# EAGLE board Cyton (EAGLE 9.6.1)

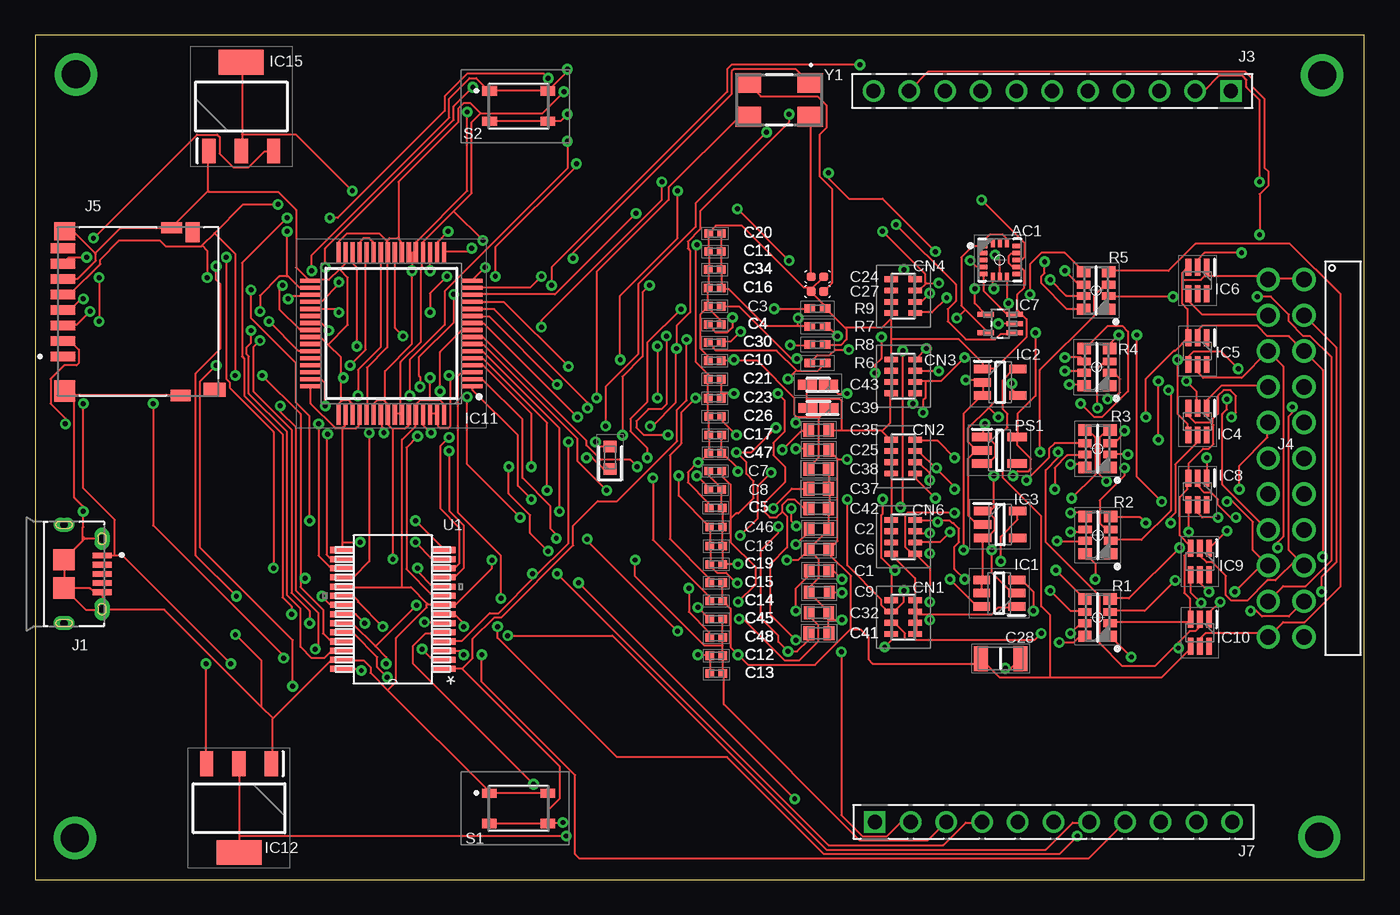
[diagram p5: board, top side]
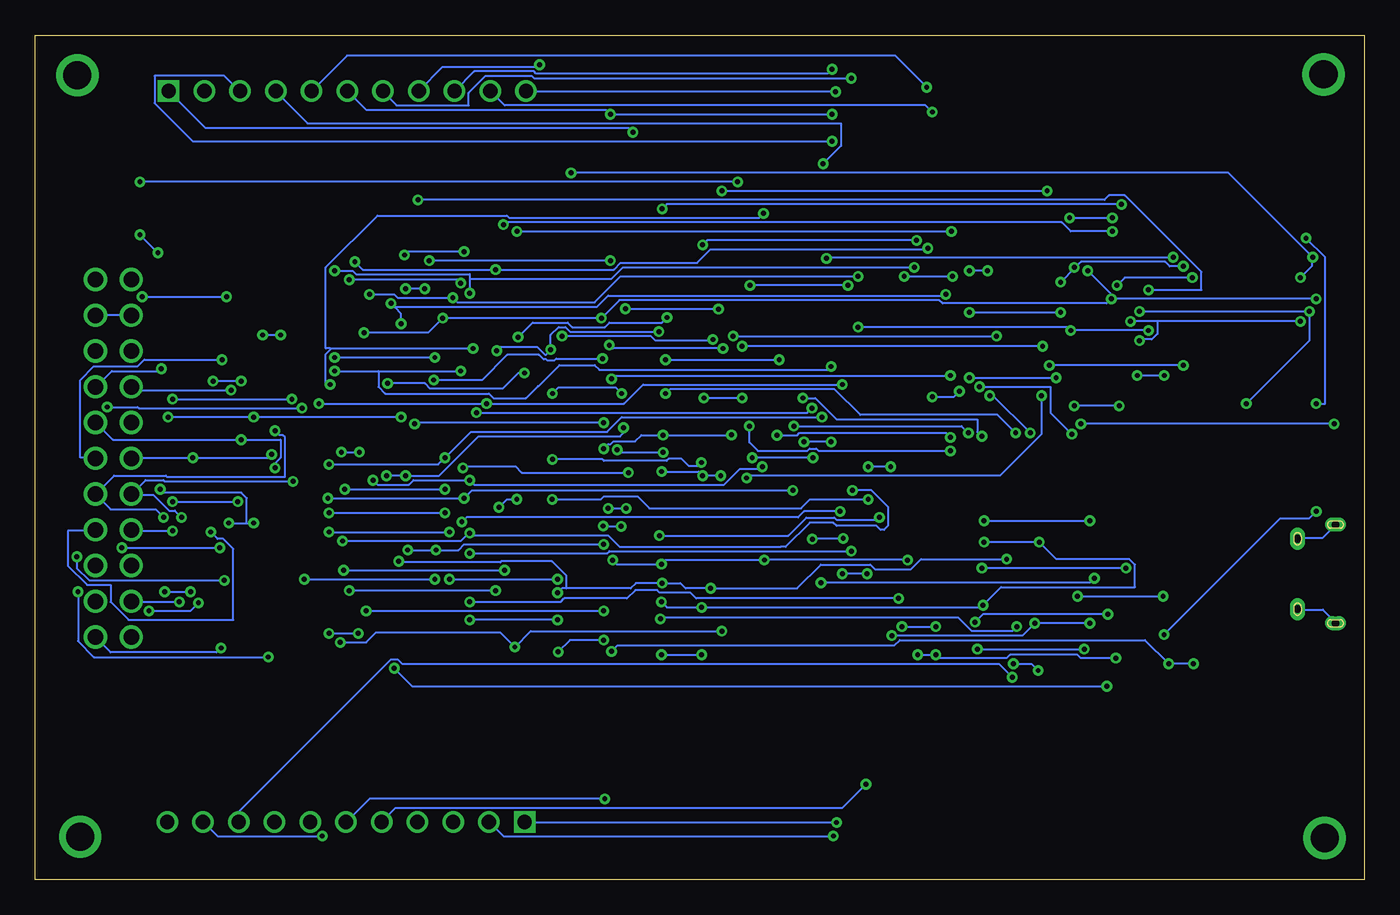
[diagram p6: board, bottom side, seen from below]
Size 94.47 x 60 mm. Coordinates in mm from the lower left corner, seen from the top.
Outline: 0,0 94.47,0 94.47,60 0,60 0,0
Copper layers (1*16): Top 0.035mm / dielectric 1.5mm / Bottom 0.035mm
Design rules "default *": minimum track width 6mil, minimum drill 0.35mm, track to track 6mil, track to pad 6mil, pad to pad 6mil, via to via 6mil, smd to smd 6mil, copper to edge 40mil, drill to drill 6mil, minimum pad ring 10mil, minimum via ring 8mil, stop-mask expansion 0mil, vias tented up to drill 100mm, thermal gap 10mil

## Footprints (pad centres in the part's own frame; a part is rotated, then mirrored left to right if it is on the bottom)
PQFN50P300X300X100-16N = smd 0.6 x 0.3: 1 -1.2,1; 2 -1.2,0.5; 3 -1.2,0; 4 -1.2,-0.5; 5 -1.2,-1; 9 1.2,-1; 10 1.2,-0.5; 11 1.2,0; 12 1.2,0.5; 13 1.2,1 | smd 0.3 x 0.6: 6 -0.5,-1.2; 7 0,-1.2; 8 0.5,-1.2; 14 0.5,1.2; 15 0,1.2; 16 -0.5,1.2
CAPC1608X90N = smd 0.75 x 0.94: 1 -0.7,0; 2 0.7,0
CAPC1005X55N = smd 0.6 x 0.62: 1 -0.46,0; 2 0.46,0
C0402 = smd 0.635 x 0.635: 1 0,0.445; 2 0,-0.445
CAPC3216X125N = smd 0.99 x 1.78: 1 -1.4,0; 2 1.4,0
CAPC1608X95N = smd 0.78 x 0.98: 1 -0.7,0; 2 0.7,0
CAPPM169X100N = smd 1.35 x 0.7: 1 -0.75,0; 2 0.75,0
CA0612KRX7R9BB102 = smd 0.95 x 0.4: 1 -0.85,1.2; 2 -0.85,0.4; 3 -0.85,-0.4; 4 -0.85,-1.2; 5 0.85,-1.2; 6 0.85,-0.4; 7 0.85,0.4; 8 0.85,1.2
SOT95P280X145-6N = smd 1.2 x 0.6: 1 -1.25,0.95; 2 -1.25,0; 3 -1.25,-0.95; 4 1.25,-0.95; 5 1.25,0; 6 1.25,0.95
SOT95P280X145-5N = smd 1.2 x 0.6: 1 -1.25,0.95; 2 -1.25,0; 3 -1.25,-0.95; 4 1.25,-0.95; 5 1.25,0.95
SOT95P280X110-5N = smd 1.25 x 0.6: 1 -1.25,0.95; 2 -1.25,0; 3 -1.25,-0.95; 4 1.25,-0.95; 5 1.25,0.95
SOT65P210X110-6N = smd 1.2 x 0.4: 1 -0.95,0.65; 2 -0.95,0; 3 -0.95,-0.65; 4 0.95,-0.65; 5 0.95,0; 6 0.95,0.65
SOT65P210X110-5N = smd 1.168 x 0.356: 1 -1.041,0.66; 2 -1.041,0; 3 -1.041,-0.66; 4 1.041,-0.66; 5 1.041,0.66
QFP50P1200X1200X120-64N = smd 1.475 x 0.3: 1 -5.738,3.75; 2 -5.738,3.25; 3 -5.738,2.75; 4 -5.738,2.25; 5 -5.738,1.75; 6 -5.738,1.25; 7 -5.738,0.75; 8 -5.738,0.25; 9 -5.738,-0.25; 10 -5.738,-0.75; 11 -5.738,-1.25; 12 -5.738,-1.75; 13 -5.738,-2.25; 14 -5.738,-2.75; 15 -5.738,-3.25; 16 -5.738,-3.75; 33 5.738,-3.75; 34 5.738,-3.25; 35 5.738,-2.75; 36 5.738,-2.25; 37 5.738,-1.75; 38 5.738,-1.25; 39 5.738,-0.75; 40 5.738,-0.25; 41 5.738,0.25; 42 5.738,0.75; 43 5.738,1.25; 44 5.738,1.75; 45 5.738,2.25; 46 5.738,2.75; 47 5.738,3.25; 48 5.738,3.75 | smd 0.3 x 1.475: 17 -3.75,-5.738; 18 -3.25,-5.738; 19 -2.75,-5.738; 20 -2.25,-5.738; 21 -1.75,-5.738; 22 -1.25,-5.738; 23 -0.75,-5.738; 24 -0.25,-5.738; 25 0.25,-5.738; 26 0.75,-5.738; 27 1.25,-5.738; 28 1.75,-5.738; 29 2.25,-5.738; 30 2.75,-5.738; 31 3.25,-5.738; 32 3.75,-5.738; 49 3.75,5.738; 50 3.25,5.738; 51 2.75,5.738; 52 2.25,5.738; 53 1.75,5.738; 54 1.25,5.738; 55 0.75,5.738; 56 0.25,5.738; 57 -0.25,5.738; 58 -0.75,5.738; 59 -1.25,5.738; 60 -1.75,5.738; 61 -2.25,5.738; 62 -2.75,5.738; 63 -3.25,5.738; 64 -3.75,5.738
SOT230P700X180-4N = smd 1.75 x 0.95: 1 -3.15,2.3; 2 -3.15,0; 3 -3.15,-2.3 | smd 1.75 x 3.2: 4 3.15,0
AMPHENOL_10118194-0001LF = smd 0.4 x 1.35: 1 -1.3,2.7; 2 -0.65,2.7; 3 0,2.7; 4 0.65,2.7; 5 1.3,2.7 | drill 0.55 pad 0.61 long: S1 -2.5,2.7; S2 2.5,2.7 | drill 0.5 pad 0.775 long: S3 -3.5,0; S6 3.5,0 | smd 1.5 x 1.55: S4 -1,0; S5 1,0
SAMTEC_SSQ-111-02-G-S = drill 1.016 square: 1 -25.4,0 | drill 1.016: 2 -22.86,0; 3 -20.32,0; 4 -17.78,0; 5 -15.24,0; 6 -12.7,0; 7 -10.16,0; 8 -7.62,0; 9 -5.08,0; 10 -2.54,0; 11 0,0
61302221021 = drill 1.1: 1 12.7,-1.27; 2 12.7,1.27; 3 10.16,-1.27; 4 10.16,1.27; 5 7.62,-1.27; 6 7.62,1.27; 7 5.08,-1.27; 8 5.08,1.27; 9 2.54,-1.27; 10 2.54,1.27; 11 0,-1.27; 12 0,1.27; 13 -2.54,-1.27; 14 -2.54,1.27; 15 -5.08,-1.27; 16 -5.08,1.27; 17 -7.62,-1.27; 18 -7.62,1.27; 19 -10.16,-1.27; 20 -10.16,1.27; 21 -12.7,-1.27; 22 -12.7,1.27
AMPHENOL_1140084168 = smd 0.7 x 1.75: 1 3.2,-0.875; 2 2.1,-0.875; 3 1,-0.875; 4 -0.1,-0.875; 5 -1.2,-0.875; 6 -2.3,-0.875; 7 -3.4,-0.875; 8 -4.5,-0.875 | smd 1 x 1.55: 9 5.575,9.925 | smd 1.45 x 1: 10 -5.625,8.35 | smd 1.5 x 1.5: S1 5.65,-0.75 | smd 1.3 x 1.5: S2 -5.7,-0.75 | smd 0.8 x 1.4: S3 5.975,7.5 | smd 0.8 x 1.5: S4 -5.95,6.85
LEDC1608X45N = smd 0.8 x 0.95: 1 -0.8,0; 2 0.8,0
SOT95P270X145-5N = smd 1.4 x 0.6: 1 -1.25,0.95; 2 -1.25,0; 3 -1.25,-0.95; 4 1.25,-0.95; 5 1.25,0.95
RESCAX80P160X320X60-8N = smd 0.95 x 0.8: 1 -0.9,1.325; 4 -0.9,-1.325; 5 0.9,-1.325; 8 0.9,1.325 | smd 0.95 x 0.55: 2 -0.9,0.4; 3 -0.9,-0.4; 6 0.9,-0.4; 7 0.9,0.4
RESC1005X40N = smd 0.75 x 0.6: 1 -0.55,0; 2 0.55,0
RESC1005X35N = smd 0.75 x 0.6: 1 -0.55,0; 2 0.55,0
PTS810SJG250SMTRLFS = smd 1.05 x 0.65: 1 -2.075,1.075; 2 2.075,1.075; 3 -2.075,-1.075; 4 2.075,-1.075
SSOP28_MC = smd 1.676 x 0.432: 1 -3.617,4.225; 2 -3.617,3.575; 3 -3.617,2.925; 4 -3.617,2.275; 5 -3.617,1.625; 6 -3.617,0.975; 7 -3.617,0.325; 8 -3.617,-0.325; 9 -3.617,-0.975; 10 -3.617,-1.625; 11 -3.617,-2.275; 12 -3.617,-2.925; 13 -3.617,-3.575; 14 -3.617,-4.225; 15 3.617,-4.225; 16 3.617,-3.575; 17 3.617,-2.925; 18 3.617,-2.275; 19 3.617,-1.625; 20 3.617,-0.975; 21 3.617,-0.325; 22 3.617,0.325; 23 3.617,0.975; 24 3.617,1.625; 25 3.617,2.275; 26 3.617,2.925; 27 3.617,3.575; 28 3.617,4.225
ABMM2 = smd 1.8 x 1.4: 1 -2.2,-1.2; 2 2.2,-1.2; 3 2.2,1.2; 4 -2.2,1.2

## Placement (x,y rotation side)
AC1  LIS3DHTR  [PQFN50P300X300X100-16N]  68.56,44.03 0 top
C1  GRM188C80G106KE47D  [CAPC1608X90N]  55.71,21.95 0 top
C2  GRM188C80G106KE47D  [CAPC1608X90N]  55.71,24.91 0 top
C3  GRM155C80J225ME95D  [CAPC1005X55N]  48.31,40.74 180 top
C4  CC0402KRX7R7BB103  [CAPC1005X55N]  48.3,39.44 0 top
C5  GRM155C80J225ME95D  [CAPC1005X55N]  48.36,26.41 0 top
C6  GRM188C80G106KE47D  [CAPC1608X90N]  55.7,23.47 180 top
C7  CC0402KRX7R7BB103  [CAPC1005X55N]  48.33,29.04 180 top
C8  GRM155C80J225ME95D  [CAPC1005X55N]  48.33,27.72 0 top
C9  GRM188C80G106KE47D  [CAPC1608X90N]  55.72,20.43 180 top
C10  GRM155R61C225KE44D  [CAPC1005X55N]  48.3,36.87 0 top
C11  GRM155C80J225ME95D  [CAPC1005X55N]  48.32,44.63 0 top
C12  GRM155R70J105KA12D  [CAPC1005X55N]  48.41,15.91 0 top
C13  GRM155R70J105KA12D  [CAPC1005X55N]  48.42,14.64 0 top
C14  GRM155R70J105KA12D  [CAPC1005X55N]  48.41,19.8 180 top
C15  GRM155R70J105KA12D  [CAPC1005X55N]  48.39,21.09 180 top
C16  CC0402KRX7R7BB104  [CAPC1005X55N]  48.3,42.03 0 top
C17  CC0402KRX7R7BB104  [CAPC1005X55N]  48.33,31.59 0 top
C18  CC0402KRX7R7BB104  [CAPC1005X55N]  48.4,23.7 180 top
C19  CC0402KRX7R7BB104  [CAPC1005X55N]  48.39,22.4 180 top
C20  GRM155C80J225ME95D  [CAPC1005X55N]  48.32,45.91 0 top
C21  GRM155R70J105KA12D  [CAPC1005X55N]  48.3,35.55 180 top
C23  CC0402KRX7R7BB104  [CAPC1005X55N]  48.3,34.2 180 top
C24  CC0402JRNPO9BN180  [C0402]  55.62,42.84 270 top
C25  GRM188C80G106KE47D  [CAPC1608X90N]  55.69,30.53 0 top
C26  CC0402KRX7R7BB104  [CAPC1005X55N]  48.32,32.9 180 top
C27  CC0402JRNPO9BN180  [C0402]  55.6,41.8 90 top
C28  CC1206MKX5R5BB107  [CAPC3216X125N]  68.62,15.71 0 top
C30  CC0402KRX7R7BB102  [CAPC1005X55N]  48.29,38.16 180 top
C32  GRM188C80G106KE47D  [CAPC1608X90N]  55.7,18.96 0 top
C34  CC0402KRX7R7BB104  [CAPC1005X55N]  48.31,43.35 0 top
C35  GRM188C80G106KE47D  [CAPC1608X90N]  55.69,31.95 180 top
C37  C0603X105J8RACTU  [CAPC1608X95N]  55.7,27.78 180 top
C38  C0603X105J8RACTU  [CAPC1608X95N]  55.7,29.18 180 top
C39  F980J107MMAAXE  [CAPPM169X100N]  55.66,33.52 180 top
C41  C0603X105J8RACTU  [CAPC1608X95N]  55.71,17.51 180 top
C42  C0603X105J8RACTU  [CAPC1608X95N]  55.7,26.37 180 top
C43  F980J107MMAAXE  [CAPPM169X100N]  55.64,35.17 180 top
C45  GRM155R70J105KA12D  [CAPC1005X55N]  48.41,18.52 180 top
C46  GRM155R70J105KA12D  [CAPC1005X55N]  48.39,25.05 180 top
C47  GRM155R70J105KA12D  [CAPC1005X55N]  48.33,30.3 0 top
C48  GRM155R70J105KA12D  [CAPC1005X55N]  48.41,17.21 180 top
CN1  CA0612KRX7R9BB102  [CA0612KRX7R9BB102]  61.7,18.66 180 top
CN2  CA0612KRX7R9BB102  [CA0612KRX7R9BB102]  61.7,30.06 0 top
CN3  CA0612KRX7R9BB102  [CA0612KRX7R9BB102]  61.7,35.76 0 top
CN4  CA0612KRX7R9BB102  [CA0612KRX7R9BB102]  61.7,41.46 0 top
CN6  CA0612KRX7R9BB102  [CA0612KRX7R9BB102]  61.7,24.36 0 top
IC1  LM2664M6_NOPB  [SOT95P280X145-6N]  68.52,20.36 180 top
IC2  TPS72325DBVR  [SOT95P280X145-5N]  68.59,35.34 0 top
IC3  TLV70025QDDCRQ1  [SOT95P280X110-5N]  68.58,25.24 0 top
IC4  TPD4E1B06DCKR  [SOT65P210X110-6N]  82.61,32.55 270 top
IC5  TPD4E1B06DCKR  [SOT65P210X110-6N]  82.61,37.56 270 top
IC6  TPD4E1B06DCKR  [SOT65P210X110-6N]  82.61,42.57 270 top
IC7  SN74LVC1G32DCKR  [SOT65P210X110-5N]  68.59,39.5 180 top
IC8  TPD4E1B06DCKR  [SOT65P210X110-6N]  82.61,27.58 270 top
IC9  TPD4E1B06DCKR  [SOT65P210X110-6N]  82.77,22.6 270 top
IC10  TPD4E1B06DCKR  [SOT65P210X110-6N]  82.78,17.55 270 top
IC11  ADS1299IPAG  [QFP50P1200X1200X120-64N]  25.31,38.8 180 top
IC12  REG1117-3.3  [SOT230P700X180-4N]  14.49,5.08 270 top
IC15  REG1117-3.3  [SOT230P700X180-4N]  14.65,54.93 90 top
J1  10118194-0001LF  [AMPHENOL_10118194-0001LF]  2.05,21.72 270 top
J3  SSQ-111-02-G-S  [SAMTEC_SSQ-111-02-G-S]  59.58,56.03 180 top
J4  61302221021  [61302221021]  88.91,29.94 90 top
J5  1140084168  [AMPHENOL_1140084168]  2.84,40.37 270 top
J7  SSQ-111-02-G-S  [SAMTEC_SSQ-111-02-G-S]  85.08,4.11 0 top
LED1  LTST-C193TBKT-5A  [LEDC1608X45N]  40.86,29.98 90 top
PS1  MCP1754T-3302E_OT  [SOT95P270X145-5N]  68.54,30.51 0 top
R1  CAY16-2201F4LF  [RESCAX80P160X320X60-8N]  75.51,18.62 180 top
R2  CAY16-2201F4LF  [RESCAX80P160X320X60-8N]  75.53,24.48 180 top
R3  CAY16-2201F4LF  [RESCAX80P160X320X60-8N]  75.5,30.62 180 top
R4  CAY16-2201F4LF  [RESCAX80P160X320X60-8N]  75.45,36.41 180 top
R5  CAY16-2201F4LF  [RESCAX80P160X320X60-8N]  75.4,41.86 180 top
R6  RC0402JR-071ML  [RESC1005X40N]  55.61,36.72 0 top
R7  RC0402JR-07470KL  [RESC1005X40N]  55.61,39.3 180 top
R8  RT0402FRE071KL  [RESC1005X35N]  55.6,38.01 180 top
R9  RT0402FRE071KL  [RESC1005X35N]  55.6,40.58 180 top
S1  PTS810SJK250SMTRLFS  [PTS810SJG250SMTRLFS]  34.36,5.07 0 top
S2  PTS810SJK250SMTRLFS  [PTS810SJG250SMTRLFS]  34.36,54.95 0 top
U1  PIC32MX250F128B_I_SS  [SSOP28_MC]  25.42,19.2 180 top
Y1  ABMM2-8.000MHZ-E2-T  [ABMM2]  52.88,55.4 180 top

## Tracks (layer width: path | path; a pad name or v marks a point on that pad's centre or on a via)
1N  (via drill 0.35)
  Top 0.152: v82.86,19.66 82.14,20.38 82.14,21.58 IC9.4 | v86.38,19.1 86.78,19.1 87.18,18.7 89.1,18.7 90.14,19.74 J4.19
  Bottom 0.152: v82.86,19.66 83.42,19.1 v86.38,19.1
1P  (via drill 0.35)
  Top 0.152: v80.86,41.42 76.38,41.42 R5.2 | v86.86,41.42 87.82,41.42 89.1,40.14 89.1,39.66 90.14,38.62 90.62,38.62 92.14,37.1 92.14,22.7 90.3,20.86 88.7,20.86 87.66,19.82 J4.20 | v84.22,19.74 83.5,19.02 83.5,18.54 IC10.1
  Bottom 0.152: v86.86,41.42 v80.86,41.42 | v84.22,19.74 87.58,19.74 J4.20
2N  (via drill 0.35)
  Top 0.152: v75.5,33.5 75.5,36.3 75.98,36.78 76.3,36.78 R4.3 | v89.34,33.58 89.34,33.18 89.1,32.94 89.1,23.42 90.14,22.38 J4.17 89.66,22.78 88.14,21.26 87.58,21.26 86.14,19.82 85.02,19.82 84.62,20.22 84.62,21.58 83.66,22.54 83.26,22.54 82.78,23.02 82.78,23.5 IC9.2
  Bottom 0.152: v75.5,33.5 87.1,33.5 87.18,33.58 v89.34,33.58
2P  (via drill 0.35)
  Top 0.152: v77.02,38.7 76.38,38.06 76.38,37.74 R4.4 | v78.3,38.7 78.3,28.62 v80.06,26.86 | v84.7,26.86 85.1,26.86 86.54,25.42 86.54,23.42 87.58,22.38 J4.18 87.34,22.54 v85.26,20.46 | v83.42,20.46 82.78,21.1 82.78,21.58 IC9.5
  Bottom 0.152: v78.3,38.7 v77.02,38.7 | v84.7,26.86 v80.06,26.86 | v85.26,20.46 v83.42,20.46
3N  (via drill 0.35)
  Top 0.152: v81.98,24.7 81.98,26.62 IC8.4
  Bottom 0.152: v81.98,24.7 81.5,24.22 81.1,24.22 80.38,23.5 80.38,18.46 87.82,18.46 89.1,19.74 89.1,20.94 90.78,20.94 92.14,22.3 92.14,24.78 90.22,24.78 J4.15
3P  (via drill 0.35)
  Top 0.152: v76.22,34.14 76.62,34.14 77.1,34.62 77.1,35.58 76.7,35.98 76.38,35.98 R4.2 | v84.7,34.14 84.7,33.42 84.38,33.1 84.38,28.06 87.58,24.86 J4.16 | v84.7,24.78 83.5,23.58 IC9.1
  Bottom 0.152: v84.7,34.14 v76.22,34.14 | v84.7,24.78 87.58,24.78 J4.16
3V3  (via drill 0.35)
  Top 0.152: 14.7,52.94 14.7,58.06 IC15.4 | 14.7,52.94 14.7,51.82 IC15.2 | PS1.3 67.34,29.58 67.74,29.58 68.22,30.06 68.22,30.94 67.74,31.42 67.34,31.42 PS1.1 67.34,31.5 67.34,32.22 v67.5,32.38 | 49.66,36.86 51.34,36.86 53.98,34.22 53.98,33.02 54.1,32.9 | 49.66,36.86 48.78,36.86 C10.2 | 54.1,32.9 54.14,32.86 55.66,32.86 | 55.66,32.86 55.74,32.86 56.38,33.5 C39.1 | 55.66,32.86 55.66,29.98 55.02,29.34 55.02,29.18 C38.2 | v54.06,32.46 54.06,32.86 54.1,32.9 | 14.7,52.94 18.54,52.94 v22.54,48.94 | v45.66,48.94 45.66,45.58 41.58,41.5 v41.58,36.94 | 49.66,36.86 v49.66,36.94
  Bottom 0.152: v67.5,32.38 67.42,32.46 v54.06,32.46 | v45.66,48.94 v22.54,48.94 | v49.66,36.94 v41.58,36.94
3V3_ESP  (via drill 0.35)
  Top 0.152: 14.54,3.1 14.54,1.98 IC12.4 | 14.54,3.1 14.54,8.22 IC12.2 | 53.1,26.14 53.1,26.62 53.5,27.02 53.98,27.02 54.62,26.38 54.94,26.38 C42.2 | 53.1,26.14 52.7,25.74 52.22,25.74 51.82,26.14 51.82,26.78 53.29,28.24 53.29,29.34 52.46,30.16 52.46,31.04 53.29,31.86 53.29,34.04 v52.78,34.54 | v57.71,34.54 57.05,34.54 C43.1 | v57.29,16.18 57.29,4.59 58.78,3.1 60.54,3.1 61.5,4.06 62.14,4.06 J7.2 | v37.74,3.1 14.54,3.1 | 53.1,26.14 53.44,25.81 53.44,23.61 52.26,22.43 52.26,18.83 v54.06,17.02
  Bottom 0.152: v57.29,16.18 56.45,17.02 v54.06,17.02 | v37.74,3.1 61.18,3.1 62.14,4.06 J7.2 | v57.71,34.54 57.27,34.97 53.22,34.97 v52.78,34.54
4N  (via drill 0.35)
  Top 0.152: v77.42,31.9 77.42,31.74 76.7,31.02 76.46,31.02 R3.3 | v85.34,25.74 84.94,25.74 84.06,26.62 84.06,27.02 83.58,27.5 83.1,27.5 82.62,27.98 82.62,28.46 IC8.2
  Bottom 0.152: v77.42,31.9 77.1,31.58 76.86,31.58 76.7,31.42 76.7,28.62 85.1,28.62 85.18,28.7 88.86,28.7 90.14,27.42 J4.13 90.14,27.34 89.1,26.3 85.9,26.3 v85.34,25.74
4P  (via drill 0.35)
  Top 0.152: v76.14,28.3 75.66,28.78 75.66,31.42 76.14,31.9 76.38,31.9 R3.4 | v84.06,25.74 82.94,25.74 82.62,26.06 IC8.5
  Bottom 0.152: v76.14,28.3 85.26,28.3 85.34,28.38 86.62,28.38 87.58,27.42 J4.14 87.58,27.34 86.06,27.34 84.94,26.22 84.54,26.22 v84.06,25.74
5N  (via drill 0.35)
  Top 0.152: v81.18,36.94 81.18,33.1 81.9,32.38 81.9,31.66 IC4.4
  Bottom 0.152: v81.18,36.94 86.7,36.94 87.18,36.46 90.3,36.46 91.26,35.5 91.26,29.98 90.22,29.98 J4.11
5P  (via drill 0.35)
  Top 0.152: v77.66,30.22 76.46,30.22 R3.2 | v83.26,29.98 83.26,28.54 IC8.1
  Bottom 0.152: v77.66,30.22 77.9,29.98 v83.26,29.98 87.58,29.98 J4.12
6N  (via drill 0.35)
  Top 0.152: v77.42,29.26 77.42,28.7 75.66,26.94 75.66,25.34 76.06,24.94 76.38,24.94 R2.3 | v81.82,35.42 82.54,34.7 82.54,33.5 IC4.2 | v79.82,31.26 v79.82,35.42
  Bottom 0.152: v77.42,29.26 77.42,29.58 77.02,29.98 77.02,31.26 v79.82,31.26 88.94,31.26 90.14,32.46 J4.9 | v79.82,35.42 v81.82,35.42
6P  (via drill 0.35)
  Top 0.152: v78.94,25.34 78.54,25.74 76.46,25.74 R2.4 | v80.7,25.34 80.7,25.74 81.02,26.06 81.02,29.5 82.54,31.02 82.54,31.58 IC4.5 | v85.58,27.74 85.58,29.42 87.58,31.42 87.58,32.46 J4.10
  Bottom 0.152: v80.7,25.34 79.42,25.34 | 79.42,25.34 v78.94,25.34 | v85.58,27.74 85.34,27.5 79.82,27.5 79.42,27.1 79.42,25.34
7N  (via drill 0.35)
  Top 0.152: v85.5,36.3 84.3,37.5 82.3,37.5 81.98,37.18 81.98,36.62 IC5.4
  Bottom 0.152: v85.5,36.3 85.66,36.14 89.02,36.14 90.14,35.02 J4.7
7P  (via drill 0.35)
  Top 0.152: v80.54,34.78 80.7,34.62 80.7,26.22 78.62,24.14 76.46,24.14 R2.2 | IC4.1 83.26,34.06 84.3,35.1 87.5,35.1 87.58,35.02 J4.8
  Bottom 0.152: v80.54,34.78 87.42,34.78 87.58,34.94 J4.8
8N  (via drill 0.35)
  Top 0.152: v81.02,21.26 78.86,19.1 76.46,19.1 R1.3 | v91.5,22.94 91.5,36.22 90.22,37.5 J4.5 90.14,37.58 89.1,38.62 87.58,38.62 86.86,39.34 82.94,39.34 82.62,39.02 82.62,38.54 IC5.2
  Bottom 0.152: v81.02,21.26 90.62,21.26 91.5,22.14 v91.5,22.94
8P  (via drill 0.35)
  Top 0.152: v81.34,23.58 77.74,19.98 76.46,19.98 R1.4 | v88.3,23.58 88.3,23.98 88.7,24.38 88.7,36.46 87.66,37.5 J4.6 87.58,37.5 85.74,35.66 83.02,35.66 82.62,36.06 82.62,36.54 IC5.5
  Bottom 0.152: v88.3,23.58 v81.34,23.58
-RAW  (via drill 0.35)
  Top 0.152: v54.06,23.82 54.94,24.7 54.94,24.86 C2.1 | v67.98,23.42 67.98,21.82 69.42,20.38 69.74,20.38 IC1.2 | v54.14,37.02 53.74,37.02 50.06,40.7 48.78,40.7 C3.1 | v66.14,35.5 67.1,35.5 67.26,35.34 IC2.2 67.34,35.26 67.34,34.46 IC2.3 67.26,34.38 65.98,33.1 v65.98,23.42
  Bottom 0.152: v54.06,23.82 63.98,23.82 64.38,23.42 v65.98,23.42 v67.98,23.42 | v54.14,37.02 57.44,37.02 57.59,36.87 58.05,36.87 58.15,36.97 58.33,36.97 58.66,37.29 60.91,37.29 62.7,35.5 v66.14,35.5
_SRB1  (via drill 0.35)
  Top 0.152: v61.74,43.34 62.38,42.7 62.54,42.7 CN4.8 | v71.74,43.9 71.74,43.1 71.5,42.86 71.5,42.38 73.34,40.54 74.46,40.54 R5.8 | v31.02,44.86 30.78,44.62 29.1,44.62 IC11.17
  Bottom 0.152: v71.74,43.9 71.18,43.34 v61.74,43.34 53.34,43.34 52.86,43.82 47.42,43.82 46.46,44.78 31.1,44.78 v31.02,44.86
_SRB2  (via drill 0.35)
  Top 0.152: v72.14,42.62 73.26,41.5 74.46,41.5 R5.7 | v64.22,42.38 63.34,42.38 63.3,42.34 | 63.3,42.34 62.86,41.9 62.62,41.9 CN4.7 | v29.34,46.06 28.62,45.34 28.62,44.62 IC11.18 | v60.22,46.06 63.26,43.02 63.26,42.38 63.3,42.34
  Bottom 0.152: v72.14,42.62 64.46,42.62 v64.22,42.38 | v60.22,46.06 v29.34,46.06
AVDD  (via drill 0.35)
  Top 0.152: v85.74,44.54 83.1,44.54 82.62,44.06 82.62,43.58 IC6.2 | v87.02,45.82 87.02,48.7 87.66,49.34 87.66,50.29 87.36,50.6 87.36,55.48 86.47,56.37 86.47,56.93 85.98,57.42 63.5,57.42 62.14,56.06 J3.10 | 26.78,44.54 27.02,44.54 IC11.21 27.1,44.62 27.1,45.34 30.7,48.94 v30.7,54.54 | 26.78,44.54 26.62,44.54 IC11.22 | v28.06,43.26 IC11.19 | 26.78,44.54 v26.78,43.26 26.78,38.06 24.86,36.14 24.86,34.06 24.82,34.02 | 24.82,34.02 25.02,33.82 25.02,33.1 IC11.56 25.1,33.02 25.1,32.3 25.34,32.06 25.42,32.06 | 24.82,34.02 24.78,34.06 24.3,34.06 24.06,33.82 24.06,33.1 IC11.54 | 25.42,32.06 26.3,32.06 26.54,32.3 26.54,33.02 IC11.59 | v47.02,28.7 47.82,27.9 47.82,27.74 C8.1 | v49.94,29 49.94,29.23 48.86,30.3 C47.2 48.78,30.38 C17.2 | v46.46,20.7 46.46,19.02 47.9,17.58 47.9,17.26 C48.2 | v49.9,21.08 49.85,21.08 49.1,21.82 48.46,21.82 47.9,22.38 C19.2 47.98,22.46 47.98,23.66 C18.2 47.98,23.74 47.98,25.02 C46.2 47.9,25.1 45.74,27.26 v45.74,28.7 | v57.34,20.38 56.46,20.38 C9.1 | v68.62,22.62 68.62,24.38 69.82,25.58 69.82,26.14 IC3.5 | v25.42,22.78 25.42,32.06
  Bottom 0.152: v87.02,45.82 v85.74,44.54 | v26.78,43.26 v28.06,43.26 | v49.94,29 47.32,29 v47.02,28.7 v45.74,28.7 | v57.34,20.38 57.02,20.7 56.7,20.7 | 56.7,20.7 52.15,20.7 51.77,21.08 v49.9,21.08 48.62,21.08 48.24,20.7 v46.46,20.7 40.32,20.7 38.64,22.38 35.1,22.38 34.78,22.06 32.22,22.06 31.5,22.78 v25.42,22.78 | v68.62,22.62 68.54,22.54 61.42,22.54 61.34,22.62 57.74,22.62 56.7,21.58 56.7,20.7 | v30.7,54.54 31.18,55.02 61.1,55.02 62.06,55.98 J3.10
AVSS  (via drill 0.35)
  Top 0.152: 47.12,29.68 47.08,29.64 | C5.1 47.82,26.46 47.82,26.78 46.38,28.22 46.38,28.94 47.08,29.64 | C13.1 47.98,14.7 47.98,15.9 C12.1 47.9,15.98 v47.1,15.98 | C15.1 48.86,21.02 48.86,19.82 C14.1 48.94,19.74 49.42,19.26 49.42,16.51 v49.95,15.98 50.67,15.26 55.42,15.26 57.94,17.78 | 57.94,17.78 57.98,17.82 57.98,21.58 56.46,23.1 56.46,23.42 C6.1 56.46,23.5 57.02,24.06 57.02,29.86 57.06,29.86 | 47.12,29.68 v47.12,29.64 47.08,29.64 | 57.06,29.86 v57.71,29.86 | 72.14,14.38 68.54,14.38 67.26,15.66 C28.1 67.18,15.74 66.8,15.35 59.52,15.35 59.23,15.65 59.23,17.22 58.7,17.74 57.98,17.74 57.94,17.78 | 72.14,14.38 80.06,14.38 82.06,16.38 82.06,16.54 IC10.4 | 72.14,14.38 72.14,18.78 71.5,19.42 71.5,25.82 68.78,28.54 68.78,31.82 69.1,32.14 69.1,33.1 68.78,33.42 68.78,35.5 69.5,36.22 69.82,36.22 IC2.5 | IC11.53 23.58,33.1 23.58,36.38 25.02,37.82 25.02,44.54 IC11.25 25.02,44.62 25.02,45.34 24.98,45.38 | 24.98,45.38 24.46,45.9 22.14,45.9 21.58,45.34 21.58,44.62 IC11.32 | 25.78,45.54 25.74,45.58 25.18,45.58 24.98,45.38 | 25.78,45.54 25.98,45.34 25.98,44.62 IC11.23 | IC11.57 25.58,33.1 25.98,33.1 IC11.58 25.98,33.18 25.98,36.78 27.42,38.22 27.42,43.5 27.5,43.58 27.5,44.54 IC11.20 27.58,44.62 27.58,45.34 29.74,47.5 | v37.58,55.98 36.06,54.46 31.66,54.46 | 31.66,54.46 31.02,53.82 31.02,48.78 29.74,47.5 | 31.66,54.46 30.94,55.18 30.46,55.18 30.06,54.78 30.06,53.82 25.82,49.58 25.82,45.58 25.78,45.54 | v47.02,45.1 46.94,45.02 46.94,36.78 47.82,35.9 47.82,35.58 C21.2 47.82,35.5 47.82,34.22 C23.2 47.82,34.14 47.82,32.94 C26.2 47.9,32.86 47.9,31.66 C17.1 47.9,31.58 47.9,30.38 C47.1 47.25,29.68 47.12,29.68
  Top 0.152: 29.74,47.5 v31.82,45.42 | 57.06,29.86 C25.2
  Bottom 0.152: v49.95,15.98 v47.1,15.98 | v37.58,55.98 59.58,55.98 J3.11 | v47.02,45.1 46.7,45.42 v31.82,45.42 | v47.12,29.64 47.37,29.39 48.01,29.39 48.53,29.9 49.43,29.9 49.58,29.75 54.05,29.75 54.16,29.86 v57.71,29.86
BIAS  (via drill 0.35)
  Top 0.152: IC6.4 81.98,41.58 81.98,41.1 82.94,40.14 87.58,40.14 J4.4 | v77.9,15.82 76.46,17.26 R1.1 | v91.42,20.46 91.42,21.5 92.46,22.54 92.46,37.82 90.22,40.06 J4.3
  Bottom 0.152: v77.9,15.82 90.3,15.82 91.42,16.94 v91.42,20.46 | J4.4 87.66,40.14 90.14,40.14 J4.3
BIAS_DRV  (via drill 0.35)
  Top 0.152: v50.14,38.94 49.42,38.22 48.78,38.22 C30.1 | v57.82,37.66 56.86,37.66 56.46,37.26 55.58,37.26 55.1,36.78 R6.1 | v72.54,21.98 74.54,19.98 R1.5 | CN1.5 60.86,19.9 60.86,21.74 v61.1,21.98 61.02,21.98 60.14,22.86 60.14,25.9 60.24,25.99 v60.24,27.03 | v61.66,37.58 61.66,26.62 v61.5,26.46
  Bottom 0.152: v50.14,38.94 56.46,38.94 56.78,39.26 57.26,39.26 57.82,38.7 v57.82,37.66 58.21,37.28 58.75,37.82 61.42,37.82 v61.66,37.58 | v72.54,21.98 v61.1,21.98 | v60.24,27.03 60.94,27.03 v61.5,26.46
BIAS_INV  (via drill 0.35)
  Top 0.152: v28.14,31.74 27.58,32.3 27.58,33.02 IC11.61 | v40.54,32.22 40.54,35.02 42.86,37.34 42.86,42.3 46.94,46.38 46.94,48.06 v51.98,53.1
  Bottom 0.152: v28.14,31.74 28.62,32.22 v40.54,32.22 | v51.98,53.1 52.3,53.42 82.38,53.42 84.94,55.98 J3.1
BOOT_EN  (via drill 0.35)
  Top 0.152: S2.3 32.3,53.9 36.38,53.9 S2.4 36.46,53.9 37.34,53.9 v37.82,54.38 | v53.66,37.98 55.02,37.98 R8.2 | v53.58,54.38 53.58,53.82 47.26,47.5 47.26,46.22 46.38,45.34 46.38,44.86 46.54,44.7 46.54,40.3 45.58,39.34 v45.58,37.74 45.5,37.66 45.5,33.87 43.86,32.23 v43.71,32.23 | v29.42,30.46 29.42,26.22 30.46,25.18 30.46,22.14 29.82,21.5 29.1,21.5 U1.11
  Bottom 0.152: v53.66,37.98 53.42,37.74 v45.58,37.74 | J3.6 72.22,55.98 70.94,54.7 53.9,54.7 v53.58,54.38 v37.82,54.38 | v29.42,30.46 38.78,30.46 38.94,30.62 39.42,30.62 39.58,30.46 43.1,30.46 43.71,31.07 v43.71,32.23
CLK  (via drill 0.35)
  Top 0.152: v21.58,40.3 21.34,40.54 IC11.37 | v28.06,40.3 28.06,41.66 v29.26,42.86 | v32.7,42.86 32.7,44.94 38.46,50.7 v38.46,50.86
  Bottom 0.152: v28.06,40.3 v21.58,40.3 | v32.7,42.86 v29.26,42.86 | v38.46,50.86 37.18,52.14 37.18,53.74 75.1,53.74 77.34,55.98 J3.4
CS1  (via drill 0.35)
  Top 0.152: v20.86,39.02 20.38,39.5 19.58,39.5 IC11.39 | v15.34,39.02 15.34,38.14 15.02,37.82 15.02,37.34 15.18,37.18 15.18,34.54 17.9,31.82 17.9,20.22 18.86,19.26 18.86,16.54 19.66,15.74 20.54,15.74 21.02,16.22 21.74,16.22 U1.26 | v87.02,49.58 87.02,55.38 86.09,56.31 86.09,56.83 85.82,57.1 84.14,57.1 83.1,56.06 82.46,56.06 J3.2 | v44.54,49.58 44.54,48.3 35.98,39.74 v35.98,39.26
  Bottom 0.152: v15.34,39.02 v20.86,39.02 21.1,39.26 v35.98,39.26 | v44.54,49.58 v87.02,49.58
CS2  (via drill 0.35)
  Top 0.152: v23.74,31.74 23.74,22.62 22.62,21.5 21.82,21.5 U1.18 | v26.62,34.38 26.62,36.94 29.1,39.42 29.1,41.82 37.82,50.54 v37.82,52.46
  Bottom 0.152: v23.74,31.74 26.38,34.38 v26.62,34.38 | v37.82,52.46 83.26,52.46 85.98,55.18 85.98,57.1 81.02,57.1 79.98,56.06 J3.3
CS3  (via drill 0.35)
  Top 0.152: v20.14,32.38 20.14,23.02 21.02,22.14 21.74,22.14 U1.17 | v2.14,32.38 2.14,32.78 1.1,33.82 1.1,35.58 2.06,36.54 2.94,36.54 3.1,36.7 3.1,37.66 2.54,38.22 1.98,38.22 J5.2
  Bottom 0.152: v2.14,32.38 v20.14,32.38
CS4  (via drill 0.35)
  Top 0.152: v69.18,40.94 69.1,41.02 69.1,42.78 AC1.8 | v68.46,39.5 69.58,39.5 IC7.2 | v20.78,31.66 20.7,31.58 20.7,23.1 21.02,22.78 21.74,22.78 U1.16 | v27.34,35.02 27.34,35.74 27.26,35.82 27.26,37.1 29.74,39.58 v29.74,41.58
  Bottom 0.152: 68.9,40.66 68.46,40.22 v68.46,39.5 | 68.9,40.66 v69.18,40.94 | v20.78,31.66 22.3,33.18 22.3,35.02 v27.34,35.02 | v29.74,41.58 29.82,41.5 53.74,41.5 54.54,40.7 68.86,40.7 68.9,40.66
D13  (via drill 0.35)
  Top 0.152: v27.66,18.3 29.02,18.3 U1.6 | v18.22,18.86 18.22,19.42 17.58,20.06 17.58,31.66 14.86,34.38 14.86,37.02 14.7,37.18 14.7,43.82 v17.9,47.02 | v20.94,47.02 21.5,47.02 29.1,54.62 29.1,55.66 30.7,57.26 36.14,57.26 v36.46,56.94
  Bottom 0.152: v27.66,18.3 27.1,18.86 v18.22,18.86 | v20.94,47.02 v17.9,47.02 | v36.46,56.94 59.02,56.94 59.18,57.1 62.46,57.1 63.66,55.9 63.66,55.02 68.78,55.02 69.74,55.98 J3.7
D18  (via drill 0.35)
  Top 0.152: v29.42,31.42 28.78,30.78 28.78,26.38 30.14,25.02 30.14,22.46 29.82,22.14 29.1,22.14 U1.12 | v41.74,31.58 41.74,35.74 43.18,37.18 43.18,41.74 v43.66,42.22 | v36.7,42.22 36.7,43.5 49.18,55.98 49.18,57.58 49.5,57.9 v58.62,57.9
  Bottom 0.152: v29.42,31.42 29.74,31.74 40.14,31.74 40.3,31.58 v41.74,31.58 | v36.7,42.22 v43.66,42.22 | v58.62,57.9 58.78,57.74 65.5,57.74 67.18,56.06 J3.8
DRDY  (via drill 0.35)
  Top 0.152: v20.62,33.66 20.62,35.26 20.38,35.5 19.58,35.5 IC11.47 | v17.42,33.66 17.42,33.26 18.54,32.14 18.54,20.54 20.14,18.94 20.14,16.62 v19.9,16.38 | v27.5,16.38 28.22,15.66 29.02,15.66 U1.2
  Bottom 0.152: v17.42,33.66 v20.62,33.66 | v27.5,16.38 v19.9,16.38
DVDD  (via drill 0.35)
  Top 0.152: 21.82,32.06 21.34,32.06 19.58,33.82 19.58,35.02 IC11.48 | 21.86,32.1 21.98,32.22 21.98,33.02 IC11.50 | 21.86,32.1 21.82,32.06 | IC11.52 23.02,33.02 23.02,32.3 22.78,32.06 21.9,32.06 21.86,32.1 | 21.82,32.06 21.82,23.98 | 21.82,23.98 21.82,23.5 U1.15 | v27.02,23.98 28.22,22.78 29.02,22.78 U1.13 | 21.82,23.98 v23.1,23.98 | v23.18,14.86 23.1,14.94 21.82,14.94 U1.28 | v24.94,15.34 24.94,15.82 24.18,16.58 | 24.18,16.58 22.54,18.22 21.82,18.22 U1.23 | v47.1,19.34 47.9,18.54 C45.2 | v49.96,19.73 51.18,20.96 51.18,22.22 49.42,23.98 49.42,25.7 | 49.42,25.7 49.42,28.06 48.86,28.62 48.86,29.02 C7.1 | v53.1,30.54 54.46,31.9 54.94,31.9 C35.2 | v27.1,19.5 24.18,16.58 | IC1.5 67.26,20.38 67.26,21.26 IC1.4 67.34,21.34 67.34,24.22 IC3.3 67.34,24.3 67.66,24.3 68.22,24.86 68.22,25.66 67.74,26.14 67.34,26.14 IC3.1 67.82,26.14 68.14,26.46 v68.14,28.7 | v69.5,28.7 69.82,29.02 70.62,29.02 70.78,29.18 70.78,29.9 69.82,30.86 69.82,31.42 PS1.5 69.82,31.5 69.82,33.1 71.1,34.38 v71.1,38.86 | AC1.14 69.02,45.26 69.02,45.58 68.78,45.82 67.82,45.82 67.42,45.42 67.42,45.1 AC1.1 67.34,45.02 66.62,45.02 65.82,44.22 65.82,40.78 66.1,40.5 | 66.1,40.5 67.5,39.1 67.5,38.86 IC7.5 | C20.2 48.78,44.7 C11.2 48.78,43.42 C34.2 48.78,42.06 C16.2 48.78,41.98 49.26,41.98 51.9,39.34 54.22,39.34 | 54.22,39.34 55.02,39.34 R7.2 | v65.5,39.9 66.1,40.5 | 54.22,39.34 v54.22,39.9 | v17.98,41.26 18.22,41.5 19.5,41.5 IC11.35 | v3.42,41.26 3.26,41.26 2.54,40.54 1.98,40.54 J5.4 | v19.66,43.26 19.66,44.38 29.42,54.14 29.42,55.5 30.86,56.94 31.34,56.94 32.22,56.06 S2.1 32.3,56.06 36.38,56.06 S2.2 36.46,56.06 37.82,57.42 v37.82,57.58
  Top 0.152: 49.42,25.7 49.49,25.7 49.81,26.03 49.98,26.03 51.06,27.1 51.06,28.32 50.54,28.83 50.54,29.65 v49.84,30.36 50.91,30.36 v52.66,32.11
  Bottom 0.152: v27.02,23.98 v23.1,23.98 21.9,22.78 16.7,22.78 16.3,22.38 16.3,20.78 25.82,20.78 v27.1,19.5 27.26,19.34 v47.1,19.34 49.57,19.34 v49.96,19.73 | v23.18,14.86 23.66,15.34 v24.94,15.34 | v53.1,30.54 52.92,30.36 v49.84,30.36 | v69.5,28.7 v68.14,28.7 65.74,28.7 62.94,31.5 52.89,31.5 52.66,31.74 v52.66,32.11 | v71.1,38.86 66.54,38.86 v65.5,39.9 v54.22,39.9 52.94,41.18 30.22,41.18 29.98,40.94 18.3,40.94 v17.98,41.26 | v3.42,41.26 v17.98,41.26 | v19.66,43.26 17.98,41.58 v17.98,41.26 | v37.82,57.58 38.14,57.26 58.86,57.26 59.02,57.42 63.26,57.42 64.62,56.06 J3.9
GND  (via drill 0.35)
  Top 0.152: CN1.1 62.62,17.5 62.62,18.22 CN1.2 62.62,18.3 62.62,18.94 CN1.3 | CN1.3 62.62,19.1 62.62,19.82 CN1.4 62.54,19.9 62.54,21.42 60.86,23.1 CN6.4 60.86,23.18 60.86,23.9 CN6.3 60.86,23.98 60.86,24.7 CN6.2 60.86,24.78 60.86,25.5 CN6.1 60.86,25.58 60.86,28.78 CN2.4 60.86,29.58 CN2.3 60.86,30.38 CN2.2 60.86,31.18 CN2.1 60.78,31.26 60.18,31.86 | 63.58,18.86 62.78,18.86 62.62,19.02 CN1.3 | 63.58,18.86 67.98,18.86 68.46,19.34 69.74,19.34 IC1.1 | C10.1 47.82,36.94 47.82,37.18 47.26,37.74 47.26,40.14 47.82,40.7 C3.2 | C3.2 47.82,40.78 47.82,41.98 C16.1 47.9,42.06 47.9,43.34 C34.1 47.9,43.42 47.9,44.62 C11.1 47.9,44.7 47.9,45.9 C20.1 47.9,45.98 48.38,46.46 50.22,46.46 54.62,42.06 55.18,42.06 C27.1 | C4.2 48.7,39.5 48.7,39.74 47.82,40.62 C3.2 | C27.1 55.18,41.82 55.18,41.98 55.98,42.78 C24.1 | C27.1 55.18,41.74 56.14,40.78 56.14,40.62 R9.1 56.22,40.54 57.56,39.2 | 57.56,39.2 57.66,39.1 57.66,38.38 57.26,37.98 56.22,37.98 R8.1 | 54.86,34.14 54.86,33.58 C39.2 | 54.86,34.14 54.86,35.1 C43.2 | CN4.1 60.86,42.62 60.86,41.9 CN4.2 60.86,41.82 60.86,41.1 CN4.3 60.86,41.02 60.86,40.3 CN4.4 60.86,40.22 60.86,39.89 | 57.34,31.9 60.14,31.9 60.18,31.86 | 57.34,31.9 56.46,31.9 C35.1 | 60.18,31.86 60.78,32.46 60.78,34.54 CN3.4 60.86,34.62 CN3.3 60.86,35.42 CN3.2 60.86,36.22 CN3.1 60.86,37.02 60.86,38.38 | 60.86,38.38 60.86,39.89 | 54.86,34.14 57.18,34.14 57.34,33.98 57.34,31.9 | R1.2 76.46,18.3 81.9,18.3 82.06,18.46 IC10.3 82.06,18.54 82.06,19.98 81.66,20.38 81.66,23.02 82.14,23.5 IC9.3 82.06,23.58 82.06,23.74 81.34,24.46 81.34,27.18 81.9,27.74 81.9,28.46 IC8.3 81.98,28.54 81.98,29.58 83.02,30.62 83.42,30.62 83.74,30.94 83.74,32.3 83.62,32.42
  Top 0.152: 83.62,32.42 83.58,32.46 82.46,32.46 81.98,32.94 81.98,33.42 IC4.3 | 81.5,42.62 81.5,43.1 81.9,43.5 IC6.3 | 81.5,42.62 81.5,40.94 81.9,40.54 81.9,38.54 IC5.3 81.9,38.46 81.02,37.58 80.94,37.58 78.94,35.58 v78.94,32.86 | 83.14,42.9 82.86,42.62 81.5,42.62 | 83.14,42.9 83.18,42.94 83.18,43.5 IC6.1 | J4.1 90.14,42.7 87.66,42.7 J4.2 87.58,42.7 87.42,42.86 83.18,42.86 83.14,42.9 | IC3.2 67.26,25.26 66.94,25.26 66.3,25.9 66.3,29.9 66.86,30.46 67.26,30.46 PS1.2 66.78,30.46 66.78,30.62 66.3,31.1 66.3,32.06 67.78,33.54 | AC1.12 69.74,44.46 69.34,44.46 69.18,44.3 69.18,43.82 69.42,43.58 69.74,43.58 AC1.10 69.82,43.5 70.06,43.5 70.3,43.26 70.3,42.06 69.82,41.58 69.82,40.46 | AC1.5 67.42,43.02 67.42,41.82 69.02,40.22 69.58,40.22 IC7.3 69.66,40.22 69.82,40.38 69.82,40.46 | 68.22,36.3 IC2.1 67.34,36.38 67.34,36.7 65.66,38.38 60.86,38.38 | 68.22,36.3 70.46,38.54 70.46,39.82 69.82,40.46 | 67.78,33.54 68.22,33.98 68.22,36.3 | 67.78,33.54 v68.46,32.86 | v85.02,32.86 85.34,33.18 85.34,34.38 84.94,34.78 84.46,34.78 84.06,34.38 84.06,33.1 83.66,32.7 83.66,32.46 83.62,32.42 | 48.86,22.7 48.86,23.66 C18.1 48.86,23.74 48.86,25.02 C46.1 48.86,25.1 48.86,26.38 C5.2 48.78,26.46 48.78,27.66 C8.2 48.86,27.74 47.9,28.7 47.9,29.02 47.89,29.04 C7.2 | 48.86,22.7 48.86,22.46 C19.1 48.85,22.42 | 56.38,18.46 56.38,17.58 C41.1 | 56.38,18.46 56.38,18.94 C32.2 56.38,19.02 55.02,20.38 C9.2 55.02,20.46 55.02,20.78 55.66,21.42 55.66,22.78 55.02,23.42 C6.2 | C6.2 55.02,23.5 56.38,24.86 C2.2 56.38,24.94 56.38,26.3 C42.1 56.46,26.38 56.46,27.74 C37.1 56.46,27.82 56.46,29.1 C38.1
  Top 0.152: v49.95,22.42 48.85,22.42 | v53.42,22.7 54.22,22.7 54.94,23.42 C6.2 | 48.86,22.7 48.85,22.42 | 48.86,16.62 48.86,15.98 C12.2 48.86,14.7 C13.2 48.94,14.62 48.94,12.46 58.62,2.78 63.42,2.78 64.7,4.06 J7.3 | 48.86,16.62 48.86,17.18 C48.1 48.86,17.26 48.86,18.46 C45.1 | 48.86,16.62 47.58,16.62 42.65,21.56 v42.65,22.71 | 21.62,43.38 21.98,43.74 21.98,44.54 IC11.31 | 21.62,43.38 20.86,42.62 19.58,42.62 IC11.33 19.5,42.62 19.42,42.62 18.54,43.5 18.54,47.58 17.26,48.86 12.3,48.86 12.26,48.9 | 21.78,34.02 21.82,34.06 22.3,34.06 22.54,33.82 22.54,33.1 IC11.51 | 21.78,34.02 21.58,33.82 21.58,33.1 IC11.49 | 20.82,38.02 21.74,37.1 21.74,35.66 | 20.82,38.02 20.3,38.54 IC11.41 | 21.74,35.66 21.74,34.06 21.78,34.02 | 21.62,43.38 22.22,42.78 22.22,39.42 20.82,38.02 | 4.26,44.5 4.3,44.46 4.3,43.98 3.02,42.7 1.98,42.7 J5.6 | 4.26,44.5 2.7,46.06 2.14,46.06 J5.S2 | 4.26,44.5 6.06,46.3 9.66,46.3 J5.S4 9.74,46.38 12.26,48.9 | 12.26,48.9 12.3,48.94 12.3,51.74 IC15.1 | 2.78,34.46 2.38,34.46 2.14,34.7 J5.S1 2.78,34.46 | 2.78,34.46 10.3,34.46 J5.S3 | J1.S5 2.06,20.78 2.06,22.7 J1.S4 2.06,22.78 3.37,24.09 | J1.S5 2.06,20.7 3.9,20.7 4.14,20.46 4.7,20.46 J1.5 4.78,20.38 4.78,19.26 J1.S2 4.78,19.18 | J1.S1 4.7,24.22 3.7,24.22 3.55,24.22 | 2.78,34.46 2.78,27.15 3.39,26.55 3.39,26.2 v3.42,26.17 3.42,25.05 3.37,25.01 3.37,24.4 | 28.06,34.06 28.78,34.06 29.02,33.82 29.02,33.1 IC11.64 | 28.06,34.06 27.34,34.06 27.1,33.82 27.1,33.1 IC11.60 27.02,33.02 27.02,32.22 26.06,31.26 26.06,20.78 | 27.86,19.62 26.7,20.78 26.06,20.78 | 27.86,19.62 27.9,19.58 29.02,19.58 U1.8 29.1,19.58 29.9,19.58 32.46,22.14 v32.46,22.7
  Top 0.152: 26.06,20.78 21.82,20.78 U1.19 | S1.2 36.38,6.14 32.3,6.14 S1.1 32.22,6.14 32.22,6.3 25.06,13.46 | 16.9,11.46 16.86,11.42 16.86,8.3 IC12.1 | 16.9,11.46 21.02,15.58 21.74,15.58 U1.27 21.82,15.58 23.34,15.58 23.82,15.1 23.82,14.7 25.06,13.46 | 25.06,13.46 25.66,14.06 25.66,17.18 27.82,19.34 27.82,19.58 27.86,19.62 | 4.78,19.18 9.18,19.18 16.07,12.29 | 16.9,11.46 16.07,12.29 | v21.9,35.66 21.74,35.66 | 28.06,34.06 v28.06,35.66 | v63.58,18.46 63.58,18.86 | 56.38,18.46 v57.34,18.46 | 57.56,39.2 60.18,39.2 60.86,39.89 | v14.23,17.41 16.07,15.57 16.07,12.29 | J1.S5 3.59,19.18 4.78,19.18 | 3.37,24.09 3.37,24.4 | 3.37,24.09 3.5,24.22 3.55,24.22 | 3.55,24.22 3.37,24.4
  Bottom 0.152: v68.46,32.86 v78.94,32.86 v85.02,32.86 | v53.42,22.7 53.14,22.42 v49.95,22.42 49.66,22.71 v42.65,22.71 32.48,22.71 v32.46,22.7 | J1.S6 2.06,18.3 2.94,19.18 4.7,19.18 J1.S2 | J1.S3 2.06,25.18 2.94,24.3 4.7,24.3 J1.S1 | v28.06,35.66 v21.9,35.66 | v57.34,18.46 v63.58,18.46 | v3.42,26.17 3.93,25.65 5.99,25.65 14.21,17.44 14.21,17.41 v14.23,17.41
IN1N  (via drill 0.35)
  Top 0.152: v64.78,41.34 63.74,40.3 62.62,40.3 CN4.5 | v70.7,41.58 70.7,43.74 71.5,44.54 73.18,44.54 74.46,43.26 R5.5 | v35.98,42.86 35.18,42.06 31.1,42.06 IC11.15
  Bottom 0.152: v70.7,41.58 68.94,41.58 68.7,41.34 v64.78,41.34 64.46,41.02 54.7,41.02 52.86,42.86 v35.98,42.86
IN1P  (via drill 0.35)
  Top 0.152: v63.58,41.66 63.02,41.1 62.62,41.1 CN4.6 | v73.18,43.26 74.14,42.3 74.46,42.3 R5.6 | v31.98,43.5 31.1,42.62 IC11.16
  Bottom 0.152: 63.58,42.7 63.58,43.02 71.66,43.02 71.9,43.26 v73.18,43.26 | 63.58,42.7 v63.58,41.66 | v31.98,43.5 52.7,43.5 53.5,42.7 63.58,42.7
IN2N  (via drill 0.35)
  Top 0.152: v64.22,36.14 62.62,36.14 CN3.7 | v73.18,36.14 74.46,36.14 74.54,36.06 R4.7 | v37.9,36.46 33.34,41.02 31.1,41.02 IC11.13
  Bottom 0.152: v73.18,36.14 70.06,36.14 | 70.06,36.14 v64.22,36.14 | v37.9,36.46 38.14,36.22 54.36,36.22 54.69,36.56 57.22,36.56 58.7,35.07 58.73,35.07 59.58,34.22 61.9,34.22 62.22,34.54 69.58,34.54 70.06,35.02 70.06,36.14
IN2P  (via drill 0.35)
  Top 0.152: v63.34,37.74 62.62,37.02 CN3.8 | v73.5,35.18 74.46,35.18 R4.8 | v42.7,47.34 36.94,41.58 31.1,41.58 IC11.14
  Bottom 0.152: v63.34,37.74 73.42,37.74 73.46,37.7 | 73.46,37.7 73.82,37.34 73.82,35.18 v73.5,35.18 | v42.7,47.34 43.02,47.02 60.78,47.02 60.94,47.18 70.14,47.18 73.82,43.5 73.82,37.74 73.5,37.74 73.46,37.7
IN3N  (via drill 0.35)
  Top 0.152: v62.38,33.82 62.54,33.98 CN3.5 | v74.3,33.82 75.26,32.86 75.82,32.86 77.66,34.7 77.66,38.94 77.26,39.34 76.22,39.34 74.62,37.74 R4.5 | v37.1,35.18 32.3,39.98 31.1,39.98 IC11.11
  Bottom 0.152: v74.3,33.82 v62.38,33.82 52.62,33.82 51.26,35.18 v37.1,35.18
IN3P  (via drill 0.35)
  Top 0.152: 63.26,35.42 64.38,35.42 v66.06,37.1 | 63.26,35.42 62.62,35.42 CN3.6 | v73.18,37.1 74.3,37.1 74.54,36.86 R4.6 | v39.26,33.5 39.26,33.9 32.62,40.54 31.1,40.54 IC11.12 | v63.1,33.18 63.1,34.06 63.26,34.22 63.26,35.42
  Bottom 0.152: v73.18,37.1 v66.06,37.1 | v39.26,33.5 39.58,33.18 v63.1,33.18
IN4N  (via drill 0.35)
  Top 0.152: 64.02,29.22 65.34,27.9 v65.34,27.74 | 64.02,29.22 62.86,30.38 62.62,30.38 CN2.7 | v72.46,27.74 72.46,29.26 73.34,30.14 74.54,30.14 R3.7 | v28.78,34.7 28.78,37.5 30.3,39.02 31.02,39.02 IC11.9 | v30.7,34.3 30.7,29.5 v34.46,25.74 | v64.06,29.26 64.02,29.22 | v50.11,24.44 51.36,25.7 51.36,27.98 v52.31,28.92
  Bottom 0.152: v72.46,27.74 v65.34,27.74 | v28.78,34.7 29.18,34.3 v30.7,34.3 | v50.11,24.44 40.93,24.44 39.65,25.72 37.68,25.72 37.51,25.56 34.64,25.56 v34.46,25.74 | v64.06,29.26 63.96,29.36 60.33,29.36 59.89,28.92 v52.31,28.92
IN4P  (via drill 0.35)
  Top 0.152: v65.34,29.98 64.14,31.18 62.62,31.18 CN2.8 | v73.58,29.5 74.38,29.5 74.54,29.34 R3.8 | v38.54,32.86 31.9,39.5 31.1,39.5 IC11.10
  Bottom 0.152: v73.58,29.5 65.82,29.5 v65.34,29.98 63.5,31.82 53.82,31.82 52.78,32.86 v38.54,32.86
IN5N  (via drill 0.35)
  Top 0.152: v63.98,27.1 62.62,28.46 62.62,28.78 CN2.5 | v73.66,27.1 75.34,28.78 75.34,31.42 74.86,31.9 74.62,31.9 R3.5 | v40.62,27.66 38.54,29.74 38.54,31.34 31.9,37.98 31.1,37.98 IC11.7
  Bottom 0.152: v73.66,27.1 v63.98,27.1 63.42,27.66 v40.62,27.66
IN5P  (via drill 0.35)
  Top 0.152: v63.58,28.38 63.58,28.86 62.86,29.58 62.62,29.58 CN2.6 | v70.46,28.38 72.06,29.98 72.06,30.62 72.46,31.02 74.54,31.02 R3.6 | v42.78,29.34 42.3,29.82 40.22,29.82 39.18,30.86 39.18,31.18 31.82,38.54 31.1,38.54 IC11.8
  Bottom 0.152: v70.46,28.38 70.14,28.06 67.9,28.06 67.58,28.38 v63.58,28.38 63.27,28.07 45.5,28.07 44.38,29.18 42.94,29.18 v42.78,29.34
IN6N  (via drill 0.35)
  Top 0.152: v72.62,24.06 R2.7 | v63.58,24.62 62.7,24.62 62.62,24.7 CN6.7 | v36.38,27.66 36.38,32.46 31.82,37.02 31.1,37.02 IC11.5
  Bottom 0.152: v72.62,24.06 64.22,24.06 63.66,24.62 v63.58,24.62 63.74,24.46 53.75,24.46 52.93,23.65 41.48,23.65 41.13,23.65 39.4,25.37 37.76,25.37 37.52,25.13 34.66,25.13 34.38,24.85 34.13,24.85 33.82,25.16 33.82,26.46 35.02,27.66 v36.38,27.66
IN6P  (via drill 0.35)
  Top 0.152: 64.14,25.5 65.02,25.5 65.18,25.34 65.26,25.34 65.66,24.94 65.66,23.98 65.34,23.66 65.34,22.06 v66.06,21.34 | 64.14,25.5 62.62,25.5 CN6.8 | v75.34,21.34 75.34,22.46 74.7,23.1 R2.8 | v37.26,26.17 37.26,32.06 31.82,37.5 31.1,37.5 IC11.6 | 64.14,25.5 v64.14,25.42
  Bottom 0.152: v75.34,21.34 v66.06,21.34 | v64.14,25.42 63.82,25.74 40.25,25.74 39.82,26.17 v37.26,26.17
IN7N  (via drill 0.35)
  Top 0.152: v65.34,26.06 61.98,26.06 61.82,25.9 61.82,23.66 62.3,23.18 62.54,23.18 CN6.5 62.62,23.1 63.58,22.14 v63.58,19.74 | v73.58,26.06 74.38,26.06 74.62,25.82 R2.5 | v33.1,19.98 33.1,23.02 30.06,26.06 30.06,35.82 30.22,35.98 31.02,35.98 IC11.3
  Bottom 0.152: v73.58,26.06 v65.34,26.06 | v33.1,19.98 47.49,19.98 47.9,20.4 50.08,20.4 50.26,20.57 51.81,20.57 52.4,19.98 56.86,19.98 57.1,19.74 v63.58,19.74
IN7P  (via drill 0.35)
  Top 0.152: 63.58,23.98 64.3,23.98 v65.02,24.7 | 63.58,23.98 62.62,23.98 CN6.6 | v73.58,24.7 74.46,24.7 R2.6 | v35.26,29.34 35.26,33.1 31.82,36.54 31.1,36.54 IC11.4 | v33.66,29.34 33.66,27.42 35.18,25.9 35.18,24.62 v36.46,23.34 | 63.58,23.98 v63.58,23.18
  Bottom 0.152: v73.58,24.7 v65.02,24.7 | v33.66,29.34 v35.26,29.34 | v36.46,23.34 53.66,23.34 53.82,23.18 v63.58,23.18
IN8N  (via drill 0.35)
  Top 0.152: v72.14,20.54 73.58,19.1 74.54,19.1 R1.6 | v61.74,20.54 61.74,19.74 61.1,19.1 60.86,19.1 CN1.6 60.78,19.1 60.54,19.1 60.14,19.5 60.14,19.9 57.72,22.32 v57.72,27.01 | v35.26,27.02 34.3,27.98 34.3,31.58 31.1,34.78 31.1,35.02 IC11.1
  Bottom 0.152: v61.74,20.54 v72.14,20.54 | v57.72,27.01 54.26,27.01 54.03,27.24 51.67,27.24 50.82,26.39 40.04,26.39 39.4,27.02 v35.26,27.02
IN8P  (via drill 0.35)
  Top 0.152: v72.78,16.86 73.82,16.86 74.22,17.26 74.54,17.26 R1.8 | CN1.8 60.85,17.01 v60.38,16.53 | v37.04,24.24 37.04,24.53 36.62,24.94 36.62,26.54 34.62,28.54 34.62,32.7 31.82,35.5 31.1,35.5 IC11.2 | v39.23,24.19 39.23,24.09 v45.66,17.66
  Bottom 0.152: v72.78,16.86 70.94,16.86 70.24,17.56 61.41,17.56 v60.38,16.53 59.24,17.66 v45.66,17.66 | v39.23,24.19 39.18,24.24 v37.04,24.24
INT1  (via drill 0.35)
  Top 0.152: v67.26,48.3 70.3,45.26 70.3,44.22 70.14,44.06 69.82,44.06 AC1.11 | v15.34,41.9 15.34,39.9 18.54,36.7 18.54,33.9 19.5,32.94 v19.5,25.5 | v27.02,25.5 29.02,23.5 U1.14
  Bottom 0.152: v67.26,48.3 18.46,48.3 18.14,48.62 17.02,48.62 11.58,43.18 11.58,41.9 v15.34,41.9 | v27.02,25.5 v19.5,25.5
MCLR  (via drill 0.35)
  Top 0.152: S1.3 32.3,3.98 36.38,3.98 S1.4 | v57.02,38.62 56.38,39.26 56.22,39.26 R7.1 | v46.3,38.38 46.3,34.06 45.63,33.39 45.63,31.15 41.37,26.89 39.97,26.89 38.24,25.16 38.24,23.76 33.1,18.62 32.62,18.62 31.1,17.1 31.1,15.74 30.38,15.02 30.3,15.02 | 30.3,15.02 29.1,15.02 U1.1 | 30.3,15.02 37.26,8.06 37.26,5.74 36.46,4.94 36.46,4.06 S1.4 | v37.5,4.06 36.54,4.06 S1.4
  Bottom 0.152: v57.02,38.62 50.7,38.62 50.38,38.3 46.38,38.3 v46.3,38.38 | v37.5,4.06 59.66,4.06 J7.1
MISO  (via drill 0.35)
  Top 0.152: v68.22,44.38 68.54,44.06 68.54,42.86 AC1.7 | v63.98,44.62 60.22,48.38 57.82,48.38 56.38,49.82 v56.38,50.22 | v3.66,44.22 2.38,44.22 1.98,43.82 J5.7 | v16.62,39.66 18.7,37.58 19.5,37.58 IC11.43 | v4.54,42.78 v4.54,39.66 | v23.42,18.22 22.78,18.86 21.82,18.86 U1.22 | v19.5,18.22 19.5,19.1 18.22,20.38 18.22,31.98 15.5,34.7 15.5,37.82 v15.98,38.3 | v33.58,17.34 41.02,17.34 56.22,2.14 71.82,2.14 73.74,4.06 74.86,4.06 J7.7
  Bottom 0.152: v68.22,44.38 67.98,44.62 v63.98,44.62 | v56.38,50.22 9.66,50.22 v3.66,44.22 3.74,44.22 3.74,43.58 v4.54,42.78 | v4.54,39.66 14.7,39.66 | 14.7,39.66 v16.62,39.66 | v19.5,18.22 v23.42,18.22 24.3,17.34 v33.58,17.34 | v15.98,38.3 15.9,38.38 15.1,38.38 14.7,38.78 14.7,39.66
MOSI  (via drill 0.35)
  Top 0.152: v30.46,15.98 30.22,16.22 29.1,16.22 U1.3 | v31.74,15.98 31.74,14.06 38.38,7.42 38.38,1.82 38.7,1.5 74.86,1.5 77.42,4.06 J7.8 | v61.18,46.54 65.42,42.3 65.42,41.1 64.86,40.54 64.86,39.66 66.14,38.38 68.22,38.38 68.62,38.78 69.58,38.78 IC7.1 | v17.9,46.06 17.9,42.94 17.94,42.9 | 17.94,42.9 18.78,42.06 19.5,42.06 IC11.34 | v3.9,40.38 2.94,39.42 1.98,39.42 J5.3 | v15.98,40.38 15.98,41.5 17.34,42.86 17.9,42.86 17.94,42.9 | v17.66,15.74 17.66,15.9 8.38,25.18 v8.38,33.82
  Bottom 0.152: v31.74,15.98 v30.46,15.98 30.22,15.74 25.42,15.74 25.18,15.98 20.38,15.98 20.14,15.74 v17.66,15.74 | v61.18,46.54 61.02,46.7 21.5,46.7 20.86,46.06 v17.9,46.06 | v15.98,40.38 v3.9,40.38 3.9,38.3 v8.38,33.82
N$1  (via drill 2 pad 3)
  other vias: 2.9,57.21
N$2  (via drill 0.35)
  Top 0.152: v49.56,39.94 49.56,39.24 49.18,38.86 48.38,38.86 48.22,39.02 48.22,39.1 47.9,39.42 C4.1 | v60.14,38.55 60.14,37.02 59.7,36.57 v59.7,36 | v69.42,35.26 69.42,34.86 69.82,34.46 IC2.4
  Bottom 0.152: v49.56,39.94 49.92,39.58 53.66,39.58 53.98,39.26 56.3,39.26 56.62,39.58 59.11,39.58 v60.14,38.55 | v69.42,35.26 66.76,35.26 66.39,34.89 61.24,34.89 60.14,36 v59.7,36
N$3  (via drill 2 pad 3)
  other vias: 2.82,2.97
N$4  (via drill 0.35)
  Top 0.152: v57.34,21.34 56.78,21.9 56.46,21.9 C1.2 | v65.02,21.34 66.94,19.42 IC1.6
  Bottom 0.152: v65.02,21.34 v57.34,21.34
N$5  (via drill 0.35)
  Top 0.152: v54.06,19.1 54.06,20.7 54.94,21.58 54.94,21.9 C1.1 | v70.94,19.1 70.94,20.46 70.14,21.26 69.82,21.26 IC1.3
  Bottom 0.152: v70.94,19.1 v54.06,19.1
N$6
  Top 0.152: C27.2 56.06,41.82 56.62,42.38 56.62,49.1 55.74,49.98 55.74,52.94 56.22,53.42 56.22,55.02 55.58,55.66 51.58,55.66 50.7,56.54 Y1.2
N$7  (via drill 0.35)
  Top 0.152: v68.14,41.98 68.06,42.06 68.06,42.78 AC1.6 | v66.78,41.98 66.78,40.94 67.5,40.22 IC7.4
  Bottom 0.152: v66.78,41.98 v68.14,41.98
N$8  (via drill 2 pad 3)
  other vias: 91.26,3.05
N$9  (via drill 2 pad 3)
  other vias: 91.47,57.16
N$11
  Top 0.152: C24.2 55.1,42.86 55.1,54.14 Y1.4
N$12  (via drill 0.35)
  Top 0.152: v71.5,17.5 71.02,17.02 61.98,17.02 61.82,17.18 61.82,17.5 61.1,18.22 60.86,18.22 CN1.7 | v73.58,17.5 74.3,18.22 74.54,18.22 R1.7
  Bottom 0.152: v73.58,17.5 v71.5,17.5
N$15  (via drill 0.35)
  Top 0.152: v27.18,31.5 26.38,30.7 26.38,22.06 28.22,20.22 29.02,20.22 U1.9 | v39.9,34.22 39.9,43.18 45.02,48.3 45.02,49.18 49.98,54.14 50.62,54.14 Y1.3
  Bottom 0.152: v27.18,31.5 27.5,31.82 27.5,32.7 37.5,32.7 39.02,34.22 v39.9,34.22
N$16  (via drill 0.35)
  Top 0.152: v27.18,22.14 27.18,21.9 28.22,20.86 29.02,20.86 U1.10 | v16.94,22.14 16.94,31.82 13.82,34.94 13.82,35.34 13.58,35.58 v13.58,44.22 | v38.22,44.14 38.22,44.54 49.5,55.82 49.5,57.42 49.66,57.58 54.06,57.58 55.02,56.62 Y1.1
  Bottom 0.152: v16.94,22.14 v27.18,22.14 | v13.58,44.22 38.14,44.22 v38.22,44.14
N$18  (via drill 0.35)
  Top 0.152: v50.04,18.53 50.32,18.53 53.26,15.58 54.3,15.58 55.66,16.94 55.66,18.06 55.02,18.7 55.02,18.94 C32.1 | v24.7,17.98 22.94,19.74 22.94,19.82 22.62,20.14 21.82,20.14 U1.20
  Bottom 0.152: v24.7,17.98 25.02,17.66 27.9,17.66 28.86,18.62 49.94,18.62 v50.04,18.53
N$32  (via drill 0.35)
  Top 0.152: v52.52,40.57 55.04,40.57 R9.2 | v45.9,40.54 43.5,38.14 43.5,33.94 42.31,32.75 42.31,31.87 43.5,30.68 v43.5,29.98 | v39.18,29.98 39.58,29.98 40.38,29.18 LED1.1
  Bottom 0.152: v52.52,40.57 45.93,40.57 v45.9,40.54 | v39.18,29.98 v43.5,29.98
N$36  (via drill 0.35)
  Top 0.152: 48.78,34.54 48.78,34.22 C23.1 | 48.78,34.54 48.78,35.5 C21.1 | v49.66,34.54 48.78,34.54 | v24.78,31.74 24.78,32.06 24.62,32.22 24.62,33.02 IC11.55
  Bottom 0.152: v49.66,34.54 49.34,34.86 37.66,34.86 35.82,33.02 26.06,33.02 v24.78,31.74
N$39  (via drill 0.35)
  Top 0.152: v49.85,31.59 48.82,32.61 C26.1 | v54.06,30.62 54.86,30.62 54.94,30.54 C25.1 | v26.14,38.62 25.58,39.18 25.58,44.54 IC11.24 | v44.86,38.62 44.86,33.77 44.52,33.43 43.58,33.43 42.73,32.58 42.73,32.12 43.25,31.6 v44.98,31.6
  Bottom 0.152: v54.06,30.62 53.74,30.94 53.56,30.94 53.35,31.15 51.83,31.15 51.39,31.59 v49.85,31.59 44.99,31.59 v44.98,31.6 | v44.86,38.62 v26.14,38.62
N$42  (via drill 0.35)
  Top 0.152: v22.38,36.54 23.5,37.66 23.5,44.54 IC11.28 | v12.86,36.54 11.74,35.42 11.74,23.58 18.3,17.02 v18.3,13.74 | v68.94,15.02 69.34,15.02 69.98,15.66 C28.2
  Bottom 0.152: v12.86,36.54 v22.38,36.54 | v18.3,13.74 67.66,13.74 v68.94,15.02
N$43  (via drill 0.35)
  Top 0.152: v44.22,37.9 v44.22,34.22 | v22.86,37.9 22.86,43.5 22.62,43.74 22.62,44.54 IC11.30 | C15.2 47.9,21.1 47.9,21.42 45.1,24.22 45.1,30.14 45.88,30.92 45.88,30.97 45.94,31.02 45.94,33.22 v46.94,34.22
  Bottom 0.152: v44.22,34.22 v46.94,34.22 | v22.86,37.9 v44.22,37.9
N$57  (via drill 0.35)
  Top 0.152: IC11.62 28.06,33.1 28.54,33.1 IC11.63 28.62,33.02 28.62,32.22 28.78,32.06 29.34,32.06 29.5,32.22 29.5,35.74 v29.42,35.82 | 54.1,36.18 54.14,36.14 55.58,36.14 56.14,36.7 R6.2 | 54.1,36.18 52.7,37.58 48.38,37.58 48.22,37.74 48.22,37.82 47.9,38.14 C30.2 | 54.1,36.18 v53.5,35.58
  Bottom 0.152: v29.42,35.82 53.26,35.82 v53.5,35.58
N$97  (via drill 0.35)
  Top 0.152: v43.9,28.54 43.9,24.14 47.9,20.14 47.9,19.82 C14.2 | v22.94,34.38 22.94,36.22 24.54,37.82 24.54,44.54 IC11.26
  Bottom 0.152: v43.9,28.54 43.74,28.7 25.9,28.7 22.94,31.66 v22.94,34.38
NC
  Top 0.152: IC11.29 23.1,44.62 23.1,45.34 23.34,45.58 23.74,45.58 23.98,45.34 23.98,44.62 IC11.27
PGC  (via drill 0.35)
  Top 0.152: v35.42,6.78 26.86,15.34 26.86,16.62 27.74,17.5 29.02,17.5 U1.5
  Bottom 0.152: v35.42,6.78 37.1,5.1 68.86,5.1 69.82,4.14 J7.5
PGD  (via drill 0.35)
  Top 0.152: LED1.2 40.14,30.78 v39.82,31.1 | v37.9,31.1 37.9,23.9 35.54,21.54 | 35.54,21.54 32.94,18.94 32.3,18.94 30.3,16.94 29.1,16.94 U1.4 | v37.1,21.74 56.38,2.46 64.54,2.46 66.14,4.06 67.26,4.06 J7.4 | 35.54,21.54 v35.34,21.74
  Bottom 0.152: v37.9,31.1 v39.82,31.1 | v35.34,21.74 v37.1,21.74
RESET  (via drill 0.35)
  Top 0.152: v21.58,42.46 21.58,42.3 20.38,41.1 19.58,41.1 IC11.36 | v12.86,43.58 12.86,42.62 13.18,42.3 13.18,37.74 11.42,35.98 11.42,23.02 v14.3,20.14 | v20.38,20.14 20.94,19.58 21.74,19.58 U1.21 | v31.1,56.3 29.74,54.94 29.74,53.98 20.62,44.86 v20.62,43.5
  Bottom 0.152: 20.58,43.46 20.14,43.9 14.14,43.9 13.82,43.58 v12.86,43.58 | 20.58,43.46 v21.58,42.46 | v20.38,20.14 v14.3,20.14 | v31.1,56.3 33.34,58.54 72.3,58.54 74.78,56.06 J3.5 | v20.62,43.5 20.58,43.46
RXD  (via drill 0.35)
  Top 0.152: v25.02,14.38 24.3,15.1 24.3,15.82 22.62,17.5 21.82,17.5 U1.24
  Bottom 0.152: v25.02,14.38 25.98,15.34 68.38,15.34 68.7,15.66 69.18,15.66 79.98,4.86 79.98,4.14 J7.9
SCLK  (via drill 0.35)
  Top 0.152: v66.46,43.98 66.86,43.58 67.34,43.58 AC1.4 | v49.9,47.66 v53.58,43.98 | v17.26,47.98 14.78,47.98 12.74,45.94 | 11.86,45.06 11.82,45.02 9.26,45.02 8.86,45.42 5.98,45.42 4.62,44.06 4.62,43.74 2.46,41.58 1.98,41.58 J5.5 | 11.86,45.06 12.74,45.94 | v17.58,42.22 17.34,41.98 17.34,40.54 18.78,39.1 19.5,39.1 IC11.40 | v12.22,42.78 12.22,44.7 11.86,45.06 | 18.86,21.42 18.86,33.1 v16.14,35.82 | 18.86,21.42 18.86,20.78 20.46,19.18 20.46,17.5 21.02,16.94 21.74,16.94 U1.25 | v14.22,35.82 14.22,44.46 12.74,45.94 | v38.62,21.1 v53.98,5.74 | 18.86,21.42 v19.18,21.42
  Bottom 0.152: v53.58,43.98 v66.46,43.98 | v49.9,47.66 49.58,47.98 v17.26,47.98 | v17.58,42.22 17.02,42.78 v12.22,42.78 | v14.22,35.82 v16.14,35.82 | v53.98,5.74 70.7,5.74 72.3,4.14 J7.6 | v38.62,21.1 19.5,21.1 v19.18,21.42
SRB1
  Top 0.152: R5.4 76.38,43.26 80.54,43.26 82.46,45.18 89.18,45.18 92.78,41.58 92.78,20.86 90.22,18.3 88.7,18.3 87.66,17.26 J4.22 87.58,17.26 87.34,17.5 83.18,17.5 82.78,17.1 82.78,16.62 IC10.5
SRB2  (via drill 0.35)
  Top 0.152: v71.42,30.38 71.42,36.22 75.26,40.06 75.26,41.5 75.98,42.22 76.3,42.22 R5.3 | v72.7,30.38 72.7,29.98 71.82,29.1 71.82,23.98 75.66,20.14 75.66,16.78 77.26,15.18 79.58,15.18 81.06,16.66 | 81.06,16.66 82.06,17.66 82.46,17.66 82.7,17.9 82.7,18.46 IC10.2 | 81.06,16.66 v81.26,16.46
  Bottom 0.152: v72.7,30.38 v71.42,30.38 | v81.26,16.46 81.58,16.14 89.1,16.14 90.14,17.18 J4.21
TXD  (via drill 0.35)
  Top 0.152: v30.46,17.98 30.46,18.22 29.82,18.86 29.1,18.86 U1.7 | v32.86,17.98 32.86,17.18 41.34,8.7 49.18,8.7 56.06,1.82 72.78,1.82 v74.06,3.1
  Bottom 0.152: v32.86,17.98 v30.46,17.98 | v74.06,3.1 81.5,3.1 82.46,4.06 J7.10
VBUS  (via drill 0.35)
  Top 0.152: 5.66,23.02 6.22,23.02 v13.9,15.34 | 5.66,23.02 4.78,23.02 J1.1 | v12.14,15.34 12.14,8.3 IC12.3 | v4.14,45.58 11.5,52.94 12.94,52.94 13.1,52.78 13.1,51.58 14.06,50.62 15.18,50.62 16.3,51.74 16.94,51.74 IC15.3 | v3.42,33.82 3.42,27.8 5.66,25.56 5.66,23.02 | C41.2 54.94,17.5 54.94,17.02 54.14,16.22 v53.5,16.22 52.82,16.9 52.82,17.34 51.59,18.57 51.59,23.4 52.82,24.64 v52.82,25.1 | v52.46,26.38 52.46,26.46 53.78,27.78 C37.2 | v53.74,26.38 53.74,25.48 v54.1,25.13
  Bottom 0.152: v12.14,15.34 v13.9,15.34 15.58,17.02 33.02,17.02 33.42,16.62 53.1,16.62 v53.5,16.22 | v4.14,45.58 2.78,44.22 2.78,33.82 v3.42,33.82 | v53.74,26.38 v52.46,26.38 | v54.1,25.13 52.85,25.13 v52.82,25.1

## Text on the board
space: PIC32 / RESET | AVSS | AVDD | DVDD | D18 | D13 | EN | ADS-RST | CLK | CS2 | CS1 | BIAS-INV | MCLR | 3V3 | GND | PGD | PGC | SCLK | MISO | MOSI | RXD | TXD | N/A | PIC32 / PROG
